VERSION 5.8 ;
BUSBITCHARS "[]" ;
DIVIDERCHAR "/" ;

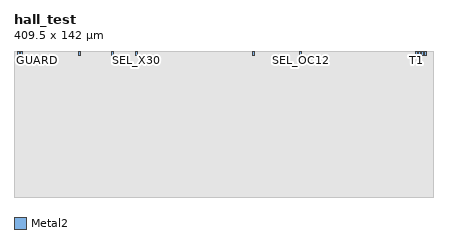
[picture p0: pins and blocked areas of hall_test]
MACRO hall_test
  CLASS BLOCK ;
  ORIGIN 0 0 ;
  FOREIGN hall_test 0 0 ;
  SIZE 409.500 BY 142.000 ;
  SYMMETRY X Y ;
  PIN GUARD
    DIRECTION INOUT ;
    USE SIGNAL ;
    PORT
      LAYER Metal2 ;
        RECT 3.000 138.000 5.000 142.000 ;
    END
  END GUARD
  PIN SEL_X12
    DIRECTION INPUT ;
    USE SIGNAL ;
    PORT
      LAYER Metal2 ;
        RECT 6.500 138.000 8.500 142.000 ;
    END
  END SEL_X12
  PIN SEL_X12P
    DIRECTION INPUT ;
    USE SIGNAL ;
    PORT
      LAYER Metal2 ;
        RECT 62.500 138.000 64.500 142.000 ;
    END
  END SEL_X12P
  PIN X12P_SH
    DIRECTION INOUT ;
    USE SIGNAL ;
    PORT
      LAYER Metal2 ;
        RECT 95.000 138.000 97.000 142.000 ;
    END
  END X12P_SH
  PIN SEL_X30
    DIRECTION INPUT ;
    USE SIGNAL ;
    PORT
      LAYER Metal2 ;
        RECT 118.500 138.000 120.500 142.000 ;
    END
  END SEL_X30
  PIN SEL_SQ30
    DIRECTION INPUT ;
    USE SIGNAL ;
    PORT
      LAYER Metal2 ;
        RECT 232.500 138.000 234.500 142.000 ;
    END
  END SEL_SQ30
  PIN SEL_OC12
    DIRECTION INPUT ;
    USE SIGNAL ;
    PORT
      LAYER Metal2 ;
        RECT 278.500 138.000 280.500 142.000 ;
    END
  END SEL_OC12
  PIN T1
    DIRECTION INOUT ;
    USE SIGNAL ;
    PORT
      LAYER Metal2 ;
        RECT 391.000 138.000 393.000 142.000 ;
    END
  END T1
  PIN T2
    DIRECTION INOUT ;
    USE SIGNAL ;
    PORT
      LAYER Metal2 ;
        RECT 394.000 138.000 396.000 142.000 ;
    END
  END T2
  PIN T3
    DIRECTION INOUT ;
    USE SIGNAL ;
    PORT
      LAYER Metal2 ;
        RECT 397.000 138.000 399.000 142.000 ;
    END
  END T3
  PIN T4
    DIRECTION INOUT ;
    USE SIGNAL ;
    PORT
      LAYER Metal2 ;
        RECT 400.000 138.000 402.000 142.000 ;
    END
  END T4
  OBS
    LAYER Metal1 ;
      RECT 0 0 409.500 142.000 ;
    LAYER Metal2 ;
      RECT 0 0 409.500 138.000 ;
    LAYER Metal3 ;
      RECT 0 0 409.500 142.000 ;
  END
END hall_test

END LIBRARY
